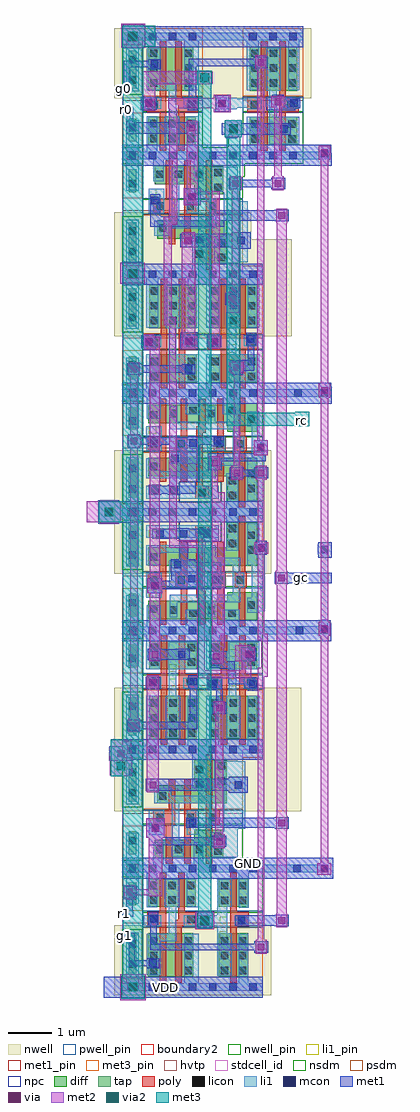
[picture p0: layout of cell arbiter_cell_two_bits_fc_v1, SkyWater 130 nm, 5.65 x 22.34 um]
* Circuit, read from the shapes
.subckt arbiter_cell_two_bits_fc_v1 GND VDD g0 g1 gc r0 r1 rc
XM1 g1 sky130_fd_sc_hd__nand2_1_13/A GND GND sky130_fd_pr__nfet_01v8 w=0.65 l=0.15
XM2 n1 sky130_fd_sc_hd__or4_1_8/A GND GND sky130_fd_pr__nfet_01v8 w=0.42 l=0.15 m=4
XM3 n2 sky130_fd_sc_hd__nand2_1_5/A GND GND sky130_fd_pr__nfet_01v8 w=0.42 l=0.15 m=4
XM4 g0 sky130_fd_sc_hd__nor2_1_1/A GND GND sky130_fd_pr__nfet_01v8 w=0.65 l=0.15
XM5 n3 sky130_fd_sc_hd__nand2_1_5/B GND GND sky130_fd_pr__nfet_01v8 w=0.65 l=0.15
XM6 n4 sky130_fd_sc_hd__or4_1_8/A GND GND sky130_fd_pr__nfet_01v8 w=0.65 l=0.15
XM7 n5 r1 GND GND sky130_fd_pr__nfet_01v8 w=0.42 l=0.15
XM8 n6 gc GND GND sky130_fd_pr__nfet_01v8 w=0.42 l=0.15
XM9 GND sky130_fd_sc_hd__nor2_1_1/A g1 GND sky130_fd_pr__nfet_01v8 w=0.65 l=0.15
XM10 GND sky130_fd_sc_hd__nand2_1_6/A g0 GND sky130_fd_pr__nfet_01v8 w=0.65 l=0.15
XM11 sky130_fd_sc_hd__or4_1_8/A sky130_fd_sc_hd__nand2_1_5/A n3 GND sky130_fd_pr__nfet_01v8 w=0.65 l=0.15
XM12 sky130_fd_sc_hd__nand2_1_5/A sky130_fd_sc_hd__nand2_1_12/A n4 GND sky130_fd_pr__nfet_01v8 w=0.65 l=0.15
XM13 GND gc n5 GND sky130_fd_pr__nfet_01v8 w=0.42 l=0.15
XM14 GND r0 n6 GND sky130_fd_pr__nfet_01v8 w=0.42 l=0.15
XM15 sky130_fd_sc_hd__nand2_1_5/B n5 GND GND sky130_fd_pr__nfet_01v8 w=0.65 l=0.15
XM16 sky130_fd_sc_hd__nand2_1_12/A n6 GND GND sky130_fd_pr__nfet_01v8 w=0.65 l=0.15
XM17 n7 r1 GND GND sky130_fd_pr__nfet_01v8 w=0.65 l=0.15
XM18 n8 r0 GND GND sky130_fd_pr__nfet_01v8 w=0.65 l=0.15
XM19 GND gc sky130_fd_sc_hd__nor2_1_1/A GND sky130_fd_pr__nfet_01v8 w=0.65 l=0.15
XM20 sky130_fd_sc_hd__nand2_1_13/A n1 GND GND sky130_fd_pr__nfet_01v8 w=0.65 l=0.15
XM21 sky130_fd_sc_hd__nand2_1_6/A n2 GND GND sky130_fd_pr__nfet_01v8 w=0.65 l=0.15
XM22 sky130_fd_sc_hd__nand2_1_15/B sky130_fd_sc_hd__nand2_1_6/A n7 GND sky130_fd_pr__nfet_01v8 w=0.65 l=0.15
XM23 sky130_fd_sc_hd__nand2_1_15/A sky130_fd_sc_hd__nand2_1_13/A n8 GND sky130_fd_pr__nfet_01v8 w=0.65 l=0.15
XM24 n9 sky130_fd_sc_hd__nand2_1_15/B GND GND sky130_fd_pr__nfet_01v8 w=0.65 l=0.15
XM25 rc sky130_fd_sc_hd__nand2_1_15/A n9 GND sky130_fd_pr__nfet_01v8 w=0.65 l=0.15
XM26 n10 sky130_fd_sc_hd__nand2_1_13/A g1 VDD sky130_fd_pr__pfet_01v8_hvt w=1 l=0.15
XM27 n11 sky130_fd_sc_hd__or4_1_8/A n1 VDD sky130_fd_pr__pfet_01v8_hvt w=0.42 l=0.15
XM28 n12 sky130_fd_sc_hd__nand2_1_5/A n2 VDD sky130_fd_pr__pfet_01v8_hvt w=0.42 l=0.15
XM29 n13 sky130_fd_sc_hd__nor2_1_1/A g0 VDD sky130_fd_pr__pfet_01v8_hvt w=1 l=0.15
XM30 sky130_fd_sc_hd__or4_1_8/A sky130_fd_sc_hd__nand2_1_5/B VDD VDD sky130_fd_pr__pfet_01v8_hvt w=1 l=0.15
XM31 sky130_fd_sc_hd__nand2_1_5/A sky130_fd_sc_hd__or4_1_8/A VDD VDD sky130_fd_pr__pfet_01v8_hvt w=1 l=0.15
XM32 n14 r1 n5 VDD sky130_fd_pr__pfet_01v8_hvt w=0.42 l=0.15
XM33 n15 gc n6 VDD sky130_fd_pr__pfet_01v8_hvt w=0.42 l=0.15
XM34 VDD sky130_fd_sc_hd__nor2_1_1/A n10 VDD sky130_fd_pr__pfet_01v8_hvt w=1 l=0.15
XM35 VDD sky130_fd_sc_hd__nand2_1_6/A n13 VDD sky130_fd_pr__pfet_01v8_hvt w=1 l=0.15
XM36 VDD sky130_fd_sc_hd__nand2_1_5/A sky130_fd_sc_hd__or4_1_8/A VDD sky130_fd_pr__pfet_01v8_hvt w=1 l=0.15
XM37 VDD sky130_fd_sc_hd__nand2_1_12/A sky130_fd_sc_hd__nand2_1_5/A VDD sky130_fd_pr__pfet_01v8_hvt w=1 l=0.15
XM38 n16 sky130_fd_sc_hd__or4_1_8/A n11 VDD sky130_fd_pr__pfet_01v8_hvt w=0.42 l=0.15
XM39 n17 sky130_fd_sc_hd__nand2_1_5/A n12 VDD sky130_fd_pr__pfet_01v8_hvt w=0.42 l=0.15
XM40 VDD gc n14 VDD sky130_fd_pr__pfet_01v8_hvt w=0.42 l=0.15
XM41 VDD r0 n15 VDD sky130_fd_pr__pfet_01v8_hvt w=0.42 l=0.15
XM42 n18 sky130_fd_sc_hd__or4_1_8/A n16 VDD sky130_fd_pr__pfet_01v8_hvt w=0.42 l=0.15
XM43 n19 sky130_fd_sc_hd__nand2_1_5/A n17 VDD sky130_fd_pr__pfet_01v8_hvt w=0.42 l=0.15
XM44 sky130_fd_sc_hd__nand2_1_5/B n5 VDD VDD sky130_fd_pr__pfet_01v8_hvt w=1 l=0.15
XM45 sky130_fd_sc_hd__nand2_1_12/A n6 VDD VDD sky130_fd_pr__pfet_01v8_hvt w=1 l=0.15
XM46 VDD sky130_fd_sc_hd__or4_1_8/A n18 VDD sky130_fd_pr__pfet_01v8_hvt w=0.42 l=0.15
XM47 VDD sky130_fd_sc_hd__nand2_1_5/A n19 VDD sky130_fd_pr__pfet_01v8_hvt w=0.42 l=0.15
XM48 sky130_fd_sc_hd__nand2_1_15/B r1 VDD VDD sky130_fd_pr__pfet_01v8_hvt w=1 l=0.15
XM49 sky130_fd_sc_hd__nand2_1_15/A r0 VDD VDD sky130_fd_pr__pfet_01v8_hvt w=1 l=0.15
XM50 VDD gc sky130_fd_sc_hd__nor2_1_1/A VDD sky130_fd_pr__pfet_01v8_hvt w=1 l=0.15
XM51 sky130_fd_sc_hd__nand2_1_13/A n1 VDD VDD sky130_fd_pr__pfet_01v8_hvt w=1 l=0.15
XM52 sky130_fd_sc_hd__nand2_1_6/A n2 VDD VDD sky130_fd_pr__pfet_01v8_hvt w=1 l=0.15
XM53 VDD sky130_fd_sc_hd__nand2_1_6/A sky130_fd_sc_hd__nand2_1_15/B VDD sky130_fd_pr__pfet_01v8_hvt w=1 l=0.15
XM54 VDD sky130_fd_sc_hd__nand2_1_13/A sky130_fd_sc_hd__nand2_1_15/A VDD sky130_fd_pr__pfet_01v8_hvt w=1 l=0.15
XM55 rc sky130_fd_sc_hd__nand2_1_15/B VDD VDD sky130_fd_pr__pfet_01v8_hvt w=1 l=0.15
XM56 VDD sky130_fd_sc_hd__nand2_1_15/A rc VDD sky130_fd_pr__pfet_01v8_hvt w=1 l=0.15
.ends

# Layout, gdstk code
from math import pi, radians
import gdstk
lib = gdstk.Library(unit=1e-6, precision=1e-09)
def R(c, l, rs):  # rectangles x0, y0, x1, y1
    for r in rs: c.add(gdstk.rectangle(r[:2], r[2:], *l))
def A(c, l, x, y, w, h, nx, ny, dx, dy):  # array of equal rectangles
    R(c, l, [(x+i*dx, y+j*dy, x+i*dx+w, y+j*dy+h) for i in range(nx) for j in range(ny)])
def P(c, l, *ps):  # polygons
    for p in ps: c.add(gdstk.Polygon(p, *l))
nwell_pin = (64, 16)
nwell = (64, 20)
diff = (65, 20)
tap = (65, 44)
poly = (66, 20)
licon = (66, 44)
li1_pin = (67, 16)
li1 = (67, 20)
mcon = (67, 44)
met1_pin = (68, 16)
met1 = (68, 20)
via = (68, 44)
met2 = (69, 20)
via2 = (69, 44)
met3_pin = (70, 16)
met3 = (70, 20)
hvtp = (78, 44)
stdcell_id = (81, 4)
nsdm = (93, 44)
psdm = (94, 20)
npc = (95, 20)
pwell_pin = (122, 16)
boundary2 = (236, 0)

sky130_fd_sc_hd__inv_1 = lib.new_cell('sky130_fd_sc_hd__inv_1')
R(sky130_fd_sc_hd__inv_1, nwell_pin, [(0.145,2.635,0.315,2.805), (0.145,2.635,0.315,2.805)])
R(sky130_fd_sc_hd__inv_1, nwell, [(-0.19,1.305,1.57,2.91)])
R(sky130_fd_sc_hd__inv_1, diff, [(0.34,0.235,1.01,0.885), (0.34,1.485,1.01,2.485)])
P(sky130_fd_sc_hd__inv_1, poly, [(0.75,2.615),(0.6,2.615),(0.6,1.325),(0.32,1.325),(0.32,0.995),(0.6,0.995),(0.6,0.105),(0.75,0.105)])
A(sky130_fd_sc_hd__inv_1, licon, 0.38, 1.575, 0.17, 0.17, 1, 3, 0, 0.34)
A(sky130_fd_sc_hd__inv_1, licon, 0.8, 1.575, 0.17, 0.17, 1, 3, 0, 0.34)
R(sky130_fd_sc_hd__inv_1, licon, [(0.38,0.315,0.55,0.485), (0.8,0.315,0.97,0.485), (0.38,0.655,0.55,0.825), (0.8,0.655,0.97,0.825), (0.4,1.075,0.57,1.245)])
R(sky130_fd_sc_hd__inv_1, li1_pin, [(0.36,1.105,0.53,1.275), (0.82,1.105,0.99,1.275), (0.82,1.445,0.99,1.615)])
R(sky130_fd_sc_hd__inv_1, li1, [(0,-0.085,1.38,0.085), (0.32,0.005,0.55,0.905), (0.32,1.075,0.65,1.315), (0.34,1.495,0.55,2.675), (0,2.635,1.38,2.805)])
P(sky130_fd_sc_hd__inv_1, li1, [(1.05,2.465),(0.72,2.465),(0.72,1.485),(0.82,1.485),(0.82,0.885),(0.72,0.885),(0.72,0.255),(1.05,0.255)])
A(sky130_fd_sc_hd__inv_1, mcon, 0.145, -0.085, 0.17, 0.17, 3, 2, 0.46, 2.72)
R(sky130_fd_sc_hd__inv_1, met1_pin, [(0.145,-0.085,0.315,0.085), (0.145,-0.085,0.315,0.085), (0.145,2.635,0.315,2.805), (0.145,2.635,0.315,2.805)])
R(sky130_fd_sc_hd__inv_1, hvtp, [(0,1.25,1.38,2.72)])
R(sky130_fd_sc_hd__inv_1, stdcell_id, [(0,0,1.38,2.72)])
R(sky130_fd_sc_hd__inv_1, nsdm, [(0,-0.19,1.38,1.015)])
R(sky130_fd_sc_hd__inv_1, psdm, [(0,1.355,1.38,2.91)])
R(sky130_fd_sc_hd__inv_1, npc, [(0,0.975,1.38,1.345)])
R(sky130_fd_sc_hd__inv_1, pwell_pin, [(0.145,-0.085,0.315,0.085), (0.145,-0.085,0.315,0.085)])
R(sky130_fd_sc_hd__inv_1, boundary2, [(0,0,1.38,2.72)])
sky130_fd_sc_hd__inv_1.add(gdstk.FlexPath([(0,2.72),(1.38,2.72)], 0.48, ends="flush", simple_path=True, layer=68, datatype=20))  # met1
sky130_fd_sc_hd__inv_1.add(gdstk.FlexPath([(0,0),(1.38,0)], 0.48, ends="flush", simple_path=True, layer=68, datatype=20))  # met1
sky130_fd_sc_hd__inv_1.add(gdstk.Label('Y', (0.905,1.53), layer=67, texttype=5))
sky130_fd_sc_hd__inv_1.add(gdstk.Label('Y', (0.905,1.19), layer=67, texttype=5))
sky130_fd_sc_hd__inv_1.add(gdstk.Label('A', (0.445,1.19), layer=67, texttype=5))
sky130_fd_sc_hd__inv_1.add(gdstk.Label('VPB', (0.23,2.72), layer=64, texttype=5))
sky130_fd_sc_hd__inv_1.add(gdstk.Label('VNB', (0.23,0), layer=64, texttype=59))
sky130_fd_sc_hd__inv_1.add(gdstk.Label('VGND', (0.23,0), layer=68, texttype=5))
sky130_fd_sc_hd__inv_1.add(gdstk.Label('VPWR', (0.23,2.72), layer=68, texttype=5))
sky130_fd_sc_hd__inv_1.add(gdstk.Label('inv_1', (0,0), layer=83, texttype=44))

sky130_fd_sc_hd__nor2_1 = lib.new_cell('sky130_fd_sc_hd__nor2_1')
R(sky130_fd_sc_hd__nor2_1, nwell_pin, [(0.15,2.635,0.32,2.805)])
R(sky130_fd_sc_hd__nor2_1, nwell, [(-0.19,1.305,1.57,2.91)])
R(sky130_fd_sc_hd__nor2_1, diff, [(0.135,0.235,1.225,0.885), (0.135,1.485,1.165,2.485)])
P(sky130_fd_sc_hd__nor2_1, poly, [(1.275,1.325),(0.905,1.325),(0.905,2.615),(0.755,2.615),(0.755,1.175),(0.815,1.175),(0.815,0.105),(0.965,0.105),(0.965,0.995),(1.275,0.995)],
  [(0.545,2.615),(0.395,2.615),(0.395,1.325),(0.11,1.325),(0.11,0.995),(0.395,0.995),(0.395,0.105),(0.545,0.105)])
A(sky130_fd_sc_hd__nor2_1, licon, 0.175, 0.305, 0.17, 0.17, 3, 2, 0.42, 0.34)
A(sky130_fd_sc_hd__nor2_1, licon, 0.175, 1.575, 0.17, 0.17, 1, 3, 0, 0.34)
A(sky130_fd_sc_hd__nor2_1, licon, 0.955, 1.575, 0.17, 0.17, 1, 3, 0, 0.34)
R(sky130_fd_sc_hd__nor2_1, licon, [(0.185,1.075,0.355,1.245), (1.025,1.075,1.195,1.245)])
R(sky130_fd_sc_hd__nor2_1, li1_pin, [(0.145,1.105,0.315,1.275), (1.065,1.105,1.235,1.275), (0.15,2.125,0.32,2.295)])
R(sky130_fd_sc_hd__nor2_1, li1, [(0.085,1.075,0.435,1.325), (0.945,1.075,1.295,1.325)])
P(sky130_fd_sc_hd__nor2_1, li1, [(1.38,0.085),(1.285,0.085),(1.285,0.895),(1.015,0.895),(1.015,0.085),(0.345,0.085),(0.345,0.895),(0.105,0.895),(0.105,0.085),(0,0.085),(0,-0.085),(1.38,-0.085)],
  [(1.38,2.805),(0,2.805),(0,2.635),(0.955,2.635),(0.955,1.495),(1.285,1.495),(1.285,2.635),(1.38,2.635)],
  [(0.845,0.895),(0.775,0.895),(0.775,1.665),(0.425,1.665),(0.425,2.45),(0.095,2.45),(0.095,1.495),(0.605,1.495),(0.605,0.895),(0.515,0.895),(0.515,0.255),(0.845,0.255)])
A(sky130_fd_sc_hd__nor2_1, mcon, 0.145, -0.085, 0.17, 0.17, 3, 2, 0.46, 2.72)
R(sky130_fd_sc_hd__nor2_1, met1_pin, [(0.15,-0.085,0.32,0.085), (0.15,2.635,0.32,2.805)])
R(sky130_fd_sc_hd__nor2_1, hvtp, [(0,1.25,1.38,2.72)])
R(sky130_fd_sc_hd__nor2_1, stdcell_id, [(0,0,1.38,2.72)])
R(sky130_fd_sc_hd__nor2_1, nsdm, [(0,-0.19,1.38,1.015)])
R(sky130_fd_sc_hd__nor2_1, psdm, [(0,1.355,1.38,2.91)])
R(sky130_fd_sc_hd__nor2_1, npc, [(0,0.975,1.38,1.345)])
R(sky130_fd_sc_hd__nor2_1, pwell_pin, [(0.15,-0.085,0.32,0.085)])
R(sky130_fd_sc_hd__nor2_1, boundary2, [(0,0,1.38,2.72)])
sky130_fd_sc_hd__nor2_1.add(gdstk.FlexPath([(0,2.72),(1.38,2.72)], 0.48, ends="flush", simple_path=True, layer=68, datatype=20))  # met1
sky130_fd_sc_hd__nor2_1.add(gdstk.FlexPath([(0,0),(1.38,0)], 0.48, ends="flush", simple_path=True, layer=68, datatype=20))  # met1
sky130_fd_sc_hd__nor2_1.add(gdstk.Label('B', (0.23,1.19), layer=67, texttype=5))
sky130_fd_sc_hd__nor2_1.add(gdstk.Label('Y', (0.235,2.21), layer=67, texttype=5))
sky130_fd_sc_hd__nor2_1.add(gdstk.Label('A', (1.15,1.19), layer=67, texttype=5))
sky130_fd_sc_hd__nor2_1.add(gdstk.Label('VPB', (0.235,2.72), layer=64, texttype=5))
sky130_fd_sc_hd__nor2_1.add(gdstk.Label('VNB', (0.235,0), layer=64, texttype=59))
sky130_fd_sc_hd__nor2_1.add(gdstk.Label('VGND', (0.23,0), layer=68, texttype=5))
sky130_fd_sc_hd__nor2_1.add(gdstk.Label('VPWR', (0.23,2.72), layer=68, texttype=5))
sky130_fd_sc_hd__nor2_1.add(gdstk.Label('nor2_1', (0,0), layer=83, texttype=44))

sky130_fd_sc_hd__or2_1 = lib.new_cell('sky130_fd_sc_hd__or2_1')
R(sky130_fd_sc_hd__or2_1, nwell_pin, [(0.145,2.635,0.315,2.805)])
R(sky130_fd_sc_hd__or2_1, nwell, [(-0.19,1.305,2.49,2.91)])
P(sky130_fd_sc_hd__or2_1, diff, [(1.855,0.885),(1.185,0.885),(1.185,0.655),(0.28,0.655),(0.28,0.235),(1.855,0.235)],
  [(1.935,2.485),(1.185,2.485),(1.185,1.905),(0.34,1.905),(0.34,1.485),(1.935,1.485)])
P(sky130_fd_sc_hd__or2_1, poly, [(0.75,2.035),(0.6,2.035),(0.6,1.325),(0.25,1.325),(0.25,0.995),(0.54,0.995),(0.54,0.105),(0.69,0.105),(0.69,0.995),(0.75,0.995)],
  [(1.775,1.325),(1.595,1.325),(1.595,2.615),(1.445,2.615),(1.445,0.105),(1.595,0.105),(1.595,0.995),(1.775,0.995)],
  [(1.23,1.325),(1.11,1.325),(1.11,2.035),(0.96,2.035),(0.96,0.105),(1.11,0.105),(1.11,0.995),(1.23,0.995)])
R(sky130_fd_sc_hd__or2_1, licon, [(1.645,0.305,1.815,0.475), (0.32,0.345,0.49,0.515), (0.74,0.345,0.91,0.515), (1.22,0.345,1.39,0.515), (1.645,0.645,1.815,0.815), (0.33,1.075,0.5,1.245), (1.01,1.075,1.18,1.245), (1.525,1.075,1.695,1.245), (0.38,1.575,0.55,1.745), (1.225,1.835,1.395,2.005), (1.725,1.915,1.895,2.085), (1.225,2.175,1.395,2.345), (1.725,2.255,1.895,2.425)])
R(sky130_fd_sc_hd__or2_1, li1_pin, [(0.145,0.765,0.315,0.935), (1.065,0.765,1.235,0.935), (0.145,1.105,0.315,1.275), (1.065,1.105,1.235,1.275), (1.985,1.785,2.155,1.955)])
R(sky130_fd_sc_hd__or2_1, li1, [(0.145,0.765,0.5,1.325), (1.01,0.765,1.275,1.325)])
P(sky130_fd_sc_hd__or2_1, li1, [(2.18,2.465),(1.645,2.465),(1.645,1.845),(1.865,1.845),(1.865,0.825),(1.565,0.825),(1.565,0.255),(2.18,0.255)],
  [(1.695,1.665),(0.66,1.665),(0.66,1.84),(0.27,1.84),(0.27,1.495),(0.67,1.495),(0.67,0.265),(0.95,0.265),(0.95,0.595),(0.84,0.595),(0.84,1.495),(1.525,1.495),(1.525,0.995),(1.695,0.995)],
  [(2.3,2.805),(0,2.805),(0,2.635),(1.145,2.635),(1.145,1.835),(1.475,1.835),(1.475,2.635),(2.3,2.635)],
  [(2.3,0.085),(1.395,0.085),(1.395,0.595),(1.18,0.595),(1.18,0.085),(0.49,0.085),(0.49,0.595),(0.25,0.595),(0.25,0.085),(0,0.085),(0,-0.085),(2.3,-0.085)])
A(sky130_fd_sc_hd__or2_1, mcon, 0.145, -0.085, 0.17, 0.17, 5, 2, 0.46, 2.72)
R(sky130_fd_sc_hd__or2_1, met1_pin, [(0.145,-0.085,0.315,0.085), (0.145,2.635,0.315,2.805)])
R(sky130_fd_sc_hd__or2_1, hvtp, [(0,1.25,2.3,2.72)])
R(sky130_fd_sc_hd__or2_1, stdcell_id, [(0,0,2.3,2.72)])
R(sky130_fd_sc_hd__or2_1, nsdm, [(0,-0.19,2.3,1.015)])
R(sky130_fd_sc_hd__or2_1, psdm, [(0,1.355,2.3,2.91)])
R(sky130_fd_sc_hd__or2_1, npc, [(0,0.975,2.3,1.345)])
R(sky130_fd_sc_hd__or2_1, pwell_pin, [(0.145,-0.085,0.315,0.085)])
R(sky130_fd_sc_hd__or2_1, boundary2, [(0,0,2.3,2.72)])
sky130_fd_sc_hd__or2_1.add(gdstk.FlexPath([(0,2.72),(2.3,2.72)], 0.48, ends="flush", simple_path=True, layer=68, datatype=20))  # met1
sky130_fd_sc_hd__or2_1.add(gdstk.FlexPath([(0,0),(2.3,0)], 0.48, ends="flush", simple_path=True, layer=68, datatype=20))  # met1
sky130_fd_sc_hd__or2_1.add(gdstk.Label('A', (1.15,1.19), layer=67, texttype=5))
sky130_fd_sc_hd__or2_1.add(gdstk.Label('X', (2.07,1.87), layer=67, texttype=5))
sky130_fd_sc_hd__or2_1.add(gdstk.Label('B', (0.23,1.19), layer=67, texttype=5))
sky130_fd_sc_hd__or2_1.add(gdstk.Label('VPB', (0.23,2.72), layer=64, texttype=5))
sky130_fd_sc_hd__or2_1.add(gdstk.Label('VNB', (0.23,0), layer=64, texttype=59))
sky130_fd_sc_hd__or2_1.add(gdstk.Label('VGND', (0.23,0), layer=68, texttype=5))
sky130_fd_sc_hd__or2_1.add(gdstk.Label('VPWR', (0.23,2.72), layer=68, texttype=5))
sky130_fd_sc_hd__or2_1.add(gdstk.Label('or2_1', (0,0), layer=83, texttype=44))

sky130_fd_sc_hd__tapvpwr = lib.new_cell('sky130_fd_sc_hd__tapvpwrvgnd_1')
R(sky130_fd_sc_hd__tapvpwr, nwell, [(-0.19,1.305,0.65,2.91)])
R(sky130_fd_sc_hd__tapvpwr, tap, [(0.145,0.32,0.315,0.845), (0.145,1.525,0.315,2.4)])
R(sky130_fd_sc_hd__tapvpwr, licon, [(0.145,0.555,0.315,0.725), (0.145,1.645,0.315,1.815), (0.145,2.11,0.315,2.28)])
R(sky130_fd_sc_hd__tapvpwr, li1, [(0,-0.085,0.46,0.085), (0.085,0,0.375,0.81), (0.085,1.47,0.375,2.72), (0,2.635,0.46,2.805)])
R(sky130_fd_sc_hd__tapvpwr, mcon, [(0.145,-0.085,0.315,0.085), (0.145,2.635,0.315,2.805)])
R(sky130_fd_sc_hd__tapvpwr, met1_pin, [(0.105,-0.09,0.36,0.1), (0.11,2.62,0.375,2.765)])
R(sky130_fd_sc_hd__tapvpwr, met1, [(0,-0.24,0.46,0.24), (0,2.48,0.46,2.96)])
R(sky130_fd_sc_hd__tapvpwr, hvtp, [(0,1.25,0.46,2.72)])
R(sky130_fd_sc_hd__tapvpwr, stdcell_id, [(0,0,0.46,2.72)])
R(sky130_fd_sc_hd__tapvpwr, nsdm, [(0,-0.19,0.46,0.19), (0,1.395,0.46,2.53)])
R(sky130_fd_sc_hd__tapvpwr, psdm, [(0,0.19,0.46,0.975), (0,2.53,0.46,2.91)])
sky130_fd_sc_hd__tapvpwr.add(gdstk.Label('VPWR', (0.23,2.72), layer=68, texttype=5))
sky130_fd_sc_hd__tapvpwr.add(gdstk.Label('VGND', (0.23,0), layer=68, texttype=5))
sky130_fd_sc_hd__tapvpwr.add(gdstk.Label('tapvpwrvgnd_1', (0,0), layer=83, texttype=44))

sky130_fd_sc_hd__nand2_1 = lib.new_cell('sky130_fd_sc_hd__nand2_1')
R(sky130_fd_sc_hd__nand2_1, nwell_pin, [(0.14,2.635,0.31,2.805)])
R(sky130_fd_sc_hd__nand2_1, nwell, [(-0.19,1.305,1.57,2.91)])
R(sky130_fd_sc_hd__nand2_1, diff, [(0.155,0.235,1.245,0.885), (0.155,1.485,1.245,2.485)])
P(sky130_fd_sc_hd__nand2_1, poly, [(1.275,1.325),(0.985,1.325),(0.985,2.615),(0.835,2.615),(0.835,0.105),(0.985,0.105),(0.985,0.995),(1.275,0.995)],
  [(0.565,2.615),(0.415,2.615),(0.415,1.325),(0.105,1.325),(0.105,0.995),(0.415,0.995),(0.415,0.105),(0.565,0.105)])
A(sky130_fd_sc_hd__nand2_1, licon, 0.195, 1.575, 0.17, 0.17, 3, 3, 0.42, 0.34)
R(sky130_fd_sc_hd__nand2_1, licon, [(0.195,0.295,0.365,0.465), (1.035,0.295,1.205,0.465), (0.195,0.635,0.365,0.805), (1.035,0.635,1.205,0.805), (0.18,1.075,0.35,1.245), (1.02,1.075,1.19,1.245)])
A(sky130_fd_sc_hd__nand2_1, li1_pin, 0.14, 1.105, 0.17, 0.17, 3, 1, 0.46, 0)
R(sky130_fd_sc_hd__nand2_1, li1_pin, [(0.6,0.425,0.77,0.595), (0.6,0.765,0.77,0.935)])
R(sky130_fd_sc_hd__nand2_1, li1, [(0.095,1.055,0.43,1.325), (0.94,1.075,1.275,1.325)])
P(sky130_fd_sc_hd__nand2_1, li1, [(1.38,0.085),(0.395,0.085),(0.395,0.885),(0.085,0.885),(0.085,0.085),(0,0.085),(0,-0.085),(1.38,-0.085)],
  [(1.38,2.805),(0,2.805),(0,2.635),(0.085,2.635),(0.085,1.495),(0.365,1.495),(0.365,2.635),(1.035,2.635),(1.035,1.495),(1.295,1.495),(1.295,2.635),(1.38,2.635)],
  [(1.295,0.885),(0.77,0.885),(0.77,1.485),(0.865,1.485),(0.865,2.465),(0.535,2.465),(0.535,1.485),(0.6,1.485),(0.6,0.255),(1.295,0.255)])
A(sky130_fd_sc_hd__nand2_1, mcon, 0.145, -0.085, 0.17, 0.17, 3, 2, 0.46, 2.72)
R(sky130_fd_sc_hd__nand2_1, met1_pin, [(0.14,-0.085,0.31,0.085), (0.14,2.635,0.31,2.805)])
R(sky130_fd_sc_hd__nand2_1, hvtp, [(0,1.25,1.38,2.72)])
R(sky130_fd_sc_hd__nand2_1, stdcell_id, [(0,0,1.38,2.72)])
R(sky130_fd_sc_hd__nand2_1, nsdm, [(0,-0.19,1.38,1.015)])
R(sky130_fd_sc_hd__nand2_1, psdm, [(0,1.355,1.38,2.91)])
R(sky130_fd_sc_hd__nand2_1, npc, [(0,0.975,1.38,1.345)])
R(sky130_fd_sc_hd__nand2_1, pwell_pin, [(0.14,-0.085,0.31,0.085)])
R(sky130_fd_sc_hd__nand2_1, boundary2, [(0,0,1.38,2.72)])
sky130_fd_sc_hd__nand2_1.add(gdstk.FlexPath([(0,2.72),(1.38,2.72)], 0.48, ends="flush", simple_path=True, layer=68, datatype=20))  # met1
sky130_fd_sc_hd__nand2_1.add(gdstk.FlexPath([(0,0),(1.38,0)], 0.48, ends="flush", simple_path=True, layer=68, datatype=20))  # met1
sky130_fd_sc_hd__nand2_1.add(gdstk.Label('Y', (0.685,0.51), layer=67, texttype=5))
sky130_fd_sc_hd__nand2_1.add(gdstk.Label('Y', (0.685,0.85), layer=67, texttype=5))
sky130_fd_sc_hd__nand2_1.add(gdstk.Label('Y', (0.685,1.19), layer=67, texttype=5))
sky130_fd_sc_hd__nand2_1.add(gdstk.Label('B', (0.225,1.19), layer=67, texttype=5))
sky130_fd_sc_hd__nand2_1.add(gdstk.Label('A', (1.145,1.19), layer=67, texttype=5))
sky130_fd_sc_hd__nand2_1.add(gdstk.Label('VPB', (0.225,2.72), layer=64, texttype=5))
sky130_fd_sc_hd__nand2_1.add(gdstk.Label('VNB', (0.225,0), layer=64, texttype=59))
sky130_fd_sc_hd__nand2_1.add(gdstk.Label('VGND', (0.23,0), layer=68, texttype=5))
sky130_fd_sc_hd__nand2_1.add(gdstk.Label('VPWR', (0.225,2.72), layer=68, texttype=5))
sky130_fd_sc_hd__nand2_1.add(gdstk.Label('nand2_1', (0,0), layer=83, texttype=44))

sky130_fd_sc_hd__or4_1 = lib.new_cell('sky130_fd_sc_hd__or4_1')
R(sky130_fd_sc_hd__or4_1, nwell_pin, [(0.15,2.635,0.32,2.805)])
R(sky130_fd_sc_hd__or4_1, nwell, [(-0.19,1.305,2.95,2.91)])
P(sky130_fd_sc_hd__or4_1, diff, [(2.625,0.885),(1.94,0.885),(1.94,0.685),(0.135,0.685),(0.135,0.265),(1.94,0.265),(1.94,0.235),(2.625,0.235)],
  [(2.625,2.485),(1.94,2.485),(1.94,1.905),(0.135,1.905),(0.135,1.485),(2.625,1.485)])
P(sky130_fd_sc_hd__or4_1, poly, [(2.39,1.325),(2.355,1.325),(2.355,2.615),(2.205,2.615),(2.205,1.325),(2.115,1.325),(2.115,0.995),(2.205,0.995),(2.205,0.105),(2.355,0.105),(2.355,0.995),(2.39,0.995)],
  [(1.905,1.325),(1.865,1.325),(1.865,2.035),(1.715,2.035),(1.715,1.325),(1.635,1.325),(1.635,0.995),(1.715,0.995),(1.715,0.135),(1.865,0.135),(1.865,0.995),(1.905,0.995)],
  [(1.535,2.415),(1.205,2.415),(1.205,2.145),(1.235,2.145),(1.235,0.76),(1.295,0.76),(1.295,0.135),(1.445,0.135),(1.445,0.905),(1.44,0.905),(1.44,0.91),(1.385,0.91),(1.385,2.145),(1.535,2.145)],
  [(1.025,2.035),(0.875,2.035),(0.875,1.325),(0.755,1.325),(0.755,0.995),(0.875,0.995),(0.875,0.135),(1.025,0.135)],
  [(0.545,2.035),(0.395,2.035),(0.395,1.325),(0.125,1.325),(0.125,0.995),(0.395,0.995),(0.395,0.135),(0.545,0.135)])
R(sky130_fd_sc_hd__or4_1, licon, [(1.075,0.315,1.245,0.485), (1.965,0.315,2.135,0.485), (0.625,0.385,0.795,0.555), (1.495,0.385,1.665,0.555), (0.175,0.415,0.345,0.585), (2.405,0.505,2.575,0.675), (0.175,1.075,0.345,1.245), (0.805,1.075,0.975,1.245), (1.685,1.075,1.855,1.245), (2.165,1.075,2.335,1.245), (0.175,1.6,0.345,1.77), (2.405,1.76,2.575,1.93), (1.98,1.915,2.15,2.085), (2.405,2.1,2.575,2.27), (1.285,2.195,1.455,2.365), (1.98,2.255,2.15,2.425)])
A(sky130_fd_sc_hd__or4_1, li1_pin, 0.15, 1.105, 0.17, 0.17, 4, 1, 0.46, 0)
A(sky130_fd_sc_hd__or4_1, li1_pin, 0.15, 2.125, 0.17, 0.17, 3, 1, 0.46, 0)
R(sky130_fd_sc_hd__or4_1, li1_pin, [(0.15,0.765,0.32,0.935), (0.61,1.445,0.78,1.615), (1.07,1.445,1.24,1.615), (2.45,1.785,2.62,1.955)])
R(sky130_fd_sc_hd__or4_1, li1, [(0.09,0.755,0.44,1.325), (0.61,0.995,1.32,1.615), (1.49,0.995,1.895,1.325), (0.09,2.125,1.745,2.415)])
P(sky130_fd_sc_hd__or4_1, li1, [(2.76,0.085),(2.215,0.085),(2.215,0.485),(1.835,0.485),(1.835,0.085),(1.325,0.085),(1.325,0.485),(0.995,0.485),(0.995,0.085),(0.425,0.085),(0.425,0.585),(0.095,0.585),(0.095,0.085),(0,0.085),(0,-0.085),(2.76,-0.085)],
  [(2.76,2.805),(0,2.805),(0,2.635),(1.915,2.635),(1.915,1.835),(2.195,1.835),(2.195,2.635),(2.76,2.635)],
  [(2.675,2.465),(2.405,2.465),(2.405,1.495),(2.505,1.495),(2.505,0.76),(2.405,0.76),(2.405,0.415),(2.675,0.415)],
  [(2.335,1.325),(2.235,1.325),(2.235,1.665),(1.68,1.665),(1.68,1.955),(0.09,1.955),(0.09,1.495),(0.41,1.495),(0.41,1.785),(1.51,1.785),(1.51,1.495),(2.065,1.495),(2.065,0.825),(0.625,0.825),(0.625,0.305),(0.795,0.305),(0.795,0.655),(1.495,0.655),(1.495,0.305),(1.665,0.305),(1.665,0.655),(2.235,0.655),(2.235,0.995),(2.335,0.995)])
A(sky130_fd_sc_hd__or4_1, mcon, 0.145, -0.085, 0.17, 0.17, 6, 2, 0.46, 2.72)
R(sky130_fd_sc_hd__or4_1, met1_pin, [(0.15,-0.085,0.32,0.085), (0.15,2.635,0.32,2.805)])
R(sky130_fd_sc_hd__or4_1, hvtp, [(0,1.25,2.76,2.72)])
R(sky130_fd_sc_hd__or4_1, stdcell_id, [(0,0,2.76,2.72)])
R(sky130_fd_sc_hd__or4_1, nsdm, [(0,-0.19,2.76,1.015)])
P(sky130_fd_sc_hd__or4_1, psdm, [(2.76,2.91),(1.81,2.91),(1.81,2.035),(0.845,2.035),(0.845,2.495),(1.81,2.495),(1.81,2.91),(0,2.91),(0,1.355),(2.76,1.355)])
R(sky130_fd_sc_hd__or4_1, npc, [(0,0.975,2.76,1.345), (0.845,2.035,1.81,2.495)])
R(sky130_fd_sc_hd__or4_1, pwell_pin, [(0.15,-0.085,0.32,0.085)])
R(sky130_fd_sc_hd__or4_1, boundary2, [(0,0,2.76,2.72)])
sky130_fd_sc_hd__or4_1.add(gdstk.FlexPath([(0,2.72),(2.76,2.72)], 0.48, ends="flush", simple_path=True, layer=68, datatype=20))  # met1
sky130_fd_sc_hd__or4_1.add(gdstk.FlexPath([(0,0),(2.76,0)], 0.48, ends="flush", simple_path=True, layer=68, datatype=20))  # met1
sky130_fd_sc_hd__or4_1.add(gdstk.Label('C', (1.155,1.19), layer=67, texttype=5))
sky130_fd_sc_hd__or4_1.add(gdstk.Label('A', (1.615,1.19), layer=67, texttype=5))
sky130_fd_sc_hd__or4_1.add(gdstk.Label('X', (2.535,1.87), layer=67, texttype=5))
sky130_fd_sc_hd__or4_1.add(gdstk.Label('C', (0.695,1.19), layer=67, texttype=5))
sky130_fd_sc_hd__or4_1.add(gdstk.Label('B', (1.155,2.21), layer=67, texttype=5))
sky130_fd_sc_hd__or4_1.add(gdstk.Label('B', (0.695,2.21), layer=67, texttype=5))
sky130_fd_sc_hd__or4_1.add(gdstk.Label('C', (0.695,1.53), layer=67, texttype=5))
sky130_fd_sc_hd__or4_1.add(gdstk.Label('B', (0.235,2.21), layer=67, texttype=5))
sky130_fd_sc_hd__or4_1.add(gdstk.Label('C', (1.155,1.53), layer=67, texttype=5))
sky130_fd_sc_hd__or4_1.add(gdstk.Label('D', (0.235,1.19), layer=67, texttype=5))
sky130_fd_sc_hd__or4_1.add(gdstk.Label('D', (0.235,0.85), layer=67, texttype=5))
sky130_fd_sc_hd__or4_1.add(gdstk.Label('VPWR', (0.235,2.72), layer=68, texttype=5))
sky130_fd_sc_hd__or4_1.add(gdstk.Label('VGND', (0.235,0), layer=68, texttype=5))
sky130_fd_sc_hd__or4_1.add(gdstk.Label('VPB', (0.235,2.72), layer=64, texttype=5))
sky130_fd_sc_hd__or4_1.add(gdstk.Label('VNB', (0.235,0), layer=64, texttype=59))
sky130_fd_sc_hd__or4_1.add(gdstk.Label('or4_1', (0,0), layer=83, texttype=44))

arbiter_cell_two_bits_fc = lib.new_cell('arbiter_cell_two_bits_fc_v1')
R(arbiter_cell_two_bits_fc, nwell, [(23.285,12.815,23.995,14.36), (23.285,14.36,23.9,14.42), (23.285,17.03,27.575,19.335), (23.285,19.335,25.39,19.78), (25.825,19.335,27.575,19.545), (25.83,19.545,27.575,19.86), (23.285,19.78,25.395,19.86), (23.285,22.47,23.995,25.3), (23.285,27.91,27.35,30.13), (23.285,30.13,23.995,30.74), (23.285,33.35,23.475,33.53), (23.9,33.35,26.81,33.53), (23.285,33.53,26.81,34.955)])
R(arbiter_cell_two_bits_fc, poly, [(26.405,19.84,26.485,19.995)])
R(arbiter_cell_two_bits_fc, li1, [(24.425,12.92,25.42,13.09), (24.095,13.47,24.265,13.64), (25.635,14.39,25.815,14.405), (24.915,14.405,25.815,14.65), (23.97,14.425,24.37,14.505), (26.115,14.445,26.29,14.62), (23.97,14.505,24.27,14.65), (24.1,14.65,24.27,14.66), (26.55,15.64,28.185,15.81), (24.08,16.49,24.39,16.8), (25.8,16.63,26.29,16.945), (25,16.68,25.175,16.855), (25.975,16.945,26.29,18.175), (25.4,19.15,25.51,19.29), (26.38,19.855,26.55,20.025), (25.465,19.86,25.635,19.99), (24.07,19.87,24.28,20.08), (24.905,19.91,25.2,20.08), (25.465,19.99,25.69,20.03), (25.51,20.03,25.69,20.04), (25.46,20.04,25.69,20.11), (25.02,20.08,25.19,20.09), (24.53,20.4,25.185,20.8), (26.1,20.45,26.27,20.555), (26.31,20.53,26.48,20.555), (26.1,20.555,26.48,20.65), (26.195,20.65,26.48,20.7), (26.195,20.7,26.405,20.745), (26.205,20.745,26.405,20.755), (23.475,21.08,27.635,21.1), (23.475,21.1,28.185,21.25), (27.345,21.25,28.185,21.27), (28.015,21.27,28.185,23.11), (26.57,21.61,26.74,22.96), (24.12,22.095,24.32,22.295), (25.52,22.25,25.69,22.42), (24.98,22.27,25.15,22.44), (24.66,22.59,24.83,22.76), (26.555,22.96,26.755,23.16), (25.34,23.295,25.51,23.325), (24.255,23.3,24.425,23.47), (24.795,23.3,24.965,23.47), (25.225,23.325,25.51,23.465), (25.225,23.465,25.34,23.47), (25.225,23.47,25.395,23.495), (23.525,23.8,26.54,23.97), (26.56,24.14,26.73,25.31), (24.515,24.295,25.425,24.465), (24.135,24.305,24.305,24.475), (24.575,24.465,24.745,24.475), (24.595,25.025,24.765,25.195), (25.455,25.28,25.815,25.36), (24.07,25.31,24.33,25.42), (26.44,25.31,26.73,25.48), (25.455,25.36,25.535,25.37), (25.455,25.37,25.795,25.42), (25.01,25.375,25.18,25.42), (24.07,25.42,25.795,25.585), (24.07,25.585,25.74,25.59), (24.07,25.59,24.33,25.755), (23.475,26.52,28.185,26.69), (24.91,27.07,25.08,27.24), (23.97,27.66,24.205,27.925), (24.88,27.67,25.13,27.92), (25.485,27.685,25.685,27.885), (26.34,27.755,26.51,27.925), (26.375,28.15,26.545,28.425), (25.89,28.65,26.105,28.865), (26.035,29.595,26.35,30.68), (25.8,30.68,26.35,30.995), (24.14,30.925,24.315,31.1), (24.945,30.97,25.21,31.235), (27.07,31.96,28.205,31.985), (23.475,31.985,28.205,32.13), (28.015,32.13,28.185,32.17), (27.075,32.555,27.275,32.755), (25.63,33.105,26.095,33.14), (23.96,33.125,24.2,33.365), (25,33.14,25.17,33.31), (25.63,33.14,26.52,33.345), (27.32,33.16,27.49,33.33), (25.63,33.345,26.095,33.365), (23.56,33.515,23.735,34.37), (24.125,34.05,24.295,34.22), (25.23,34.68,26.67,34.705), (25.17,34.705,26.67,34.825), (25.17,34.825,26.325,34.85)])
A(arbiter_cell_two_bits_fc, mcon, 23.62, 21.08, 0.17, 0.17, 1, 3, 0, 2.72)
R(arbiter_cell_two_bits_fc, mcon, [(24.095,13.47,24.265,13.64), (25.275,14.44,25.445,14.61), (26.115,14.445,26.285,14.615), (24.1,14.49,24.27,14.66), (27.39,15.64,27.56,15.81), (28.015,15.64,28.185,15.81), (24.15,16.56,24.32,16.73), (25,16.68,25.17,16.85), (26.045,17.55,26.215,17.72), (26.38,19.855,26.55,20.025), (25.465,19.86,25.635,20.03), (24.09,19.89,24.26,20.06), (25.02,19.92,25.19,20.09), (26.31,20.53,26.48,20.7), (24.75,20.535,24.92,20.705), (27.445,21.08,27.615,21.25), (28.015,21.1,28.185,21.27), (24.135,22.11,24.305,22.28), (25.52,22.25,25.69,22.42), (24.98,22.27,25.15,22.44), (24.66,22.59,24.83,22.76), (28.015,22.94,28.185,23.11), (26.57,22.975,26.74,23.145), (25.34,23.295,25.51,23.465), (24.255,23.3,24.425,23.47), (24.795,23.3,24.965,23.47), (24.135,24.305,24.305,24.475), (24.575,24.305,24.745,24.475), (24.595,25.025,24.765,25.195), (26.56,25.27,26.73,25.44), (25.01,25.375,25.18,25.545), (24.12,25.42,24.29,25.59), (25.57,25.42,25.74,25.59), (27.41,26.52,27.58,26.69), (28.015,26.52,28.185,26.69), (24.91,27.07,25.08,27.24), (24,27.69,24.17,27.86), (25.5,27.7,25.67,27.87), (24.92,27.71,25.09,27.88), (26.34,27.755,26.51,27.925), (25.91,28.67,26.08,28.84), (26.105,30.01,26.275,30.18), (24.14,30.925,24.31,31.095), (24.99,31.015,25.16,31.185), (28.015,32,28.185,32.17), (27.09,32.57,27.26,32.74), (25,33.14,25.17,33.31), (25.675,33.15,25.845,33.32), (23.995,33.16,24.165,33.33), (27.32,33.16,27.49,33.33), (24.125,34.05,24.295,34.22)])
R(arbiter_cell_two_bits_fc, met1_pin, [(24.45,12.955,24.49,13.02), (23.5,14.165,23.54,14.19), (23.505,14.665,23.535,14.71), (26.335,15.84,26.395,15.85), (27.465,22.29,27.7,22.475), (23.525,33.07,23.595,33.115), (23.49,33.58,23.51,33.595)])
R(arbiter_cell_two_bits_fc, met1, [(23.055,12.765,25.405,13.245), (24.035,13.44,24.325,13.485), (23.62,13.485,24.325,13.625), (23.62,13.625,23.76,14.105), (24.035,13.625,24.325,13.67), (26.495,13.795,26.815,13.85), (24.11,13.85,26.815,14), (24.11,14,24.26,14.43), (26.495,14,26.815,14.055), (23.475,14.105,23.76,14.245), (25.15,14.33,25.585,14.735), (26.965,14.4,27.285,14.415), (26.055,14.415,27.285,14.65), (24.07,14.43,24.3,14.72), (23.475,14.615,23.72,14.755), (26.965,14.65,27.285,14.66), (23.57,14.755,23.71,15.05), (23.48,15.05,23.8,15.31), (23.935,15.485,23.995,15.965), (26.09,15.485,28.305,15.695), (26.075,15.695,28.305,15.85), (26.09,15.85,28.305,15.92), (26.095,15.92,28.305,15.935), (26.425,15.935,28.305,15.965), (25.535,16.215,25.855,16.255), (24.085,16.255,25.855,16.42), (24.02,16.42,25.855,16.435), (24.02,16.435,24.45,16.875), (25.535,16.435,25.855,16.475), (26.965,16.635,27.285,16.65), (24.94,16.65,27.285,16.885), (26.965,16.885,27.285,16.895), (25.915,17.45,26.35,17.5), (24.01,17.5,26.35,17.77), (25.915,17.77,26.35,17.825), (23.175,18.19,23.715,18.525), (23.935,18.205,23.995,18.685), (23.475,18.525,23.505,18.685), (23.585,18.865,23.905,18.91), (23.585,18.91,25.19,19.08), (23.585,19.08,23.905,19.125), (25.02,19.08,25.19,19.86), (25.535,19.265,25.855,19.525), (25.62,19.525,25.775,19.8), (26.35,19.795,26.58,19.85), (25.435,19.8,25.765,20.09), (24.01,19.84,24.34,20.11), (26.275,19.85,26.58,19.935), (24.99,19.86,25.22,20.15), (25.91,19.935,26.58,19.95), (25.905,19.95,26.58,20.085), (25.905,20.085,26.545,20.095), (25.47,20.09,25.765,20.105), (25.905,20.095,26.4,20.1), (25.905,20.1,26.075,20.21), (25.905,20.21,26.05,20.295), (25.71,20.295,26.05,20.315), (25.49,20.315,26.05,20.44), (25.475,20.44,26.05,20.46), (25.475,20.46,25.875,20.7), (26.195,20.465,26.505,20.475), (26.195,20.475,26.545,20.775), (24.06,20.49,24.38,20.505), (24.695,20.495,25.015,20.505), (24.06,20.505,25.015,20.74), (24.06,20.74,24.38,20.75), (24.695,20.74,25.015,20.755), (26.195,20.775,26.505,20.785), (23.475,20.925,23.995,21.095), (26.465,20.925,28.255,21.03), (26.145,21.03,28.255,21.08), (26.145,21.08,28.26,21.095), (23.475,21.095,28.26,21.24), (23.475,21.24,23.995,21.405), (26.395,21.24,28.26,21.34), (26.395,21.34,28.25,21.405), (28.015,21.405,28.185,21.415), (24.045,22.02,24.395,22.11), (24.045,22.11,25.74,22.31), (26.96,22.245,27.28,22.255), (26.96,22.255,28.275,22.49), (24.045,22.31,24.395,22.37), (24.595,22.31,25.74,22.33), (24.595,22.33,25.745,22.485), (24.58,22.485,25.745,22.73), (26.96,22.49,27.28,22.505), (24.58,22.73,25.14,22.8), (24.78,22.8,24.98,23.215), (27.965,22.84,28.27,22.91), (26.525,22.9,26.785,23.22), (27.955,22.91,28.27,23.14), (27.965,23.14,28.27,23.195), (24.78,23.215,25.685,23.27), (24.165,23.27,25.685,23.495), (24.165,23.495,25.01,23.5), (24.73,23.5,25.01,23.505), (22.925,23.615,23.405,23.64), (22.925,23.64,23.73,23.645), (22.925,23.645,23.995,24.125), (25.275,24.095,25.445,24.125), (22.925,24.125,23.73,24.13), (22.925,24.13,23.405,24.155), (24.075,24.275,24.365,24.295), (24.515,24.275,24.805,24.295), (24.075,24.295,25.16,24.485), (24.075,24.485,24.365,24.505), (24.515,24.485,25.16,24.505), (24.555,24.505,25.16,24.57), (24.555,24.57,25.25,25.42), (25.94,24.65,26.26,24.705), (26.495,24.65,26.815,24.705), (25.94,24.705,26.815,24.855), (25.43,24.835,25.755,25.05), (25.94,24.855,26.26,24.91), (26.495,24.855,26.815,24.91), (25.43,25.05,26.755,25.185), (25.43,25.185,26.81,25.23), (26.48,25.23,26.81,25.52), (23.615,25.345,23.875,25.42), (24.06,25.39,24.35,25.42), (25.51,25.39,25.8,25.42), (23.615,25.42,25.8,25.59), (23.615,25.59,23.875,25.665), (24.06,25.59,24.35,25.62), (24.985,25.59,25.215,25.6), (25.51,25.59,25.8,25.62), (23.475,26.365,23.995,26.845), (26.295,26.365,28.275,26.505), (26.275,26.505,28.275,26.66), (26.525,26.66,28.275,26.69), (26.41,26.69,28.275,26.755), (26.41,26.755,28.26,26.845), (23.585,27.025,23.905,27.07), (25.97,27.03,26.23,27.115), (24.85,27.04,25.14,27.07), (23.585,27.07,25.14,27.24), (25.97,27.115,26.5,27.21), (25.935,27.21,26.5,27.36), (23.585,27.24,23.905,27.285), (24.85,27.24,25.14,27.27), (26.35,27.36,26.5,27.695), (23.94,27.6,24.235,27.63), (24.81,27.61,25.22,27.635), (23.91,27.63,24.235,27.925), (24.805,27.635,25.22,27.95), (25.425,27.655,25.745,27.915), (26.31,27.695,26.54,27.985), (23.94,27.925,24.235,27.955), (24.81,27.95,25.22,27.995), (25.86,28.59,26.135,28.62), (25.83,28.62,26.165,28.895), (25.86,28.895,26.135,28.925), (23.475,29.075,23.955,29.085), (23.475,29.085,23.995,29.565), (23.475,29.565,23.955,29.615), (25.975,29.91,26.41,29.94), (24.805,29.94,26.41,30.255), (25.975,30.255,26.41,30.285), (24.11,30.415,25.81,30.555), (26.965,30.54,27.285,30.555), (24.11,30.555,27.285,30.65), (24.11,30.65,24.345,31.16), (25.575,30.65,27.285,30.79), (26.965,30.79,27.285,30.8), (24.88,30.905,25.275,31.295), (25.91,31.275,26.23,31.32), (26.88,31.275,27.2,31.32), (25.91,31.32,27.2,31.49), (25.91,31.49,26.23,31.535), (26.88,31.49,27.2,31.535), (23.79,31.805,23.995,32.285), (26.19,31.805,28.265,31.96), (27.01,31.96,28.265,32.095), (27.01,32.095,28.26,32.285), (25.845,32.445,26.105,32.46), (25.825,32.46,26.215,32.525), (25.755,32.525,27.335,32.785), (23.575,32.535,23.725,32.54), (23.575,32.54,25.24,32.805), (25.825,32.785,26.215,32.855), (23.575,32.805,23.725,33.015), (23.475,33.015,23.73,33.165), (25.6,33.045,25.92,33.425), (24.97,33.08,25.2,33.37), (26.77,33.08,27.435,33.13), (23.9,33.095,24.26,33.395), (26.77,33.13,27.55,33.16), (26.755,33.16,27.55,33.36), (26.755,33.36,27.435,33.39), (25,33.37,25.17,34.09), (26.91,33.39,27.17,33.435), (23.475,33.53,23.665,33.68), (23.51,33.68,23.66,34.06), (24.065,34.02,24.355,34.06), (26.485,34.045,26.805,34.09), (23.51,34.06,24.355,34.21), (25,34.09,26.805,34.26), (24.065,34.21,24.355,34.25), (26.485,34.26,26.805,34.305), (23.485,34.505,23.965,34.525), (23.475,34.525,23.48,35.005), (23.485,34.525,23.995,35.005), (25.16,34.525,26.405,34.675), (24.83,34.675,26.405,34.83), (24.83,34.83,26.335,34.85), (24.83,34.85,26.405,34.92), (25.265,34.92,26.405,35.005), (23.485,35.005,23.965,35.045)])
A(arbiter_cell_two_bits_fc, via, 28.025, 21.135, 0.15, 0.15, 1, 3, 0, 5.45)
R(arbiter_cell_two_bits_fc, via, [(23.64,12.93,23.79,13.08), (26.58,13.85,26.73,14), (25.285,14.45,25.435,14.6), (27.05,14.455,27.2,14.605), (23.565,15.105,23.715,15.255), (28.025,15.635,28.175,15.785), (25.62,16.27,25.77,16.42), (24.16,16.57,24.31,16.72), (27.05,16.69,27.2,16.84), (24.1,17.56,24.25,17.71), (23.37,18.28,23.52,18.43), (23.67,18.92,23.82,19.07), (25.62,19.32,25.77,19.47), (24.1,19.9,24.25,20.05), (25.56,20.495,25.71,20.645), (24.145,20.545,24.295,20.695), (26.295,20.56,26.445,20.71), (24.145,22.12,24.295,22.27), (27.045,22.3,27.195,22.45), (26.58,22.985,26.73,23.135), (23.09,23.81,23.24,23.96), (26.025,24.705,26.175,24.855), (26.58,24.705,26.73,24.855), (25.515,24.925,25.665,25.075), (26.57,25.28,26.72,25.43), (23.67,25.43,23.82,25.58), (23.67,27.08,23.82,27.23), (26.025,27.115,26.175,27.265), (23.995,27.7,24.145,27.85), (25.51,27.71,25.66,27.86), (24.915,27.715,25.065,27.865), (25.92,28.68,26.07,28.83), (23.64,29.27,23.79,29.42), (24.915,30.02,25.065,30.17), (27.05,30.595,27.2,30.745), (25,31.025,25.15,31.175), (25.995,31.33,26.145,31.48), (26.965,31.33,27.115,31.48), (25.945,32.58,26.095,32.73), (25,32.595,25.15,32.745), (25.685,33.16,25.835,33.31), (24.005,33.17,24.155,33.32), (26.965,33.2,27.115,33.35), (26.57,34.1,26.72,34.25), (23.65,34.7,23.8,34.85)])
A(arbiter_cell_two_bits_fc, met2, 27.97, 21.05, 0.26, 0.32, 1, 3, 0, 5.45)
R(arbiter_cell_two_bits_fc, met2, [(23.425,12.71,24.015,13.295), (26.525,13.765,26.785,14.085), (26.58,14.085,26.73,20.11), (25.15,14.33,25.585,14.735), (26.995,14.37,27.255,14.69), (27.005,14.69,27.24,16.605), (23.51,15.02,23.77,15.11), (24.08,15.08,24.39,15.11), (23.51,15.11,24.39,15.25), (23.51,15.25,23.77,15.34), (24.08,15.25,24.39,16.42), (27.94,15.58,28.26,15.84), (28.015,15.84,28.185,21.05), (25.565,16.185,25.825,16.505), (24.02,16.42,24.45,16.875), (25.605,16.505,25.785,19.235), (26.995,16.605,27.255,16.925), (27.005,16.925,27.24,22.215), (24.04,17.47,24.31,20.14), (23.205,17.83,23.685,17.855), (23.185,17.855,23.705,18.285), (23.205,18.285,23.685,18.67), (23.615,18.835,23.875,19.155), (23.66,19.155,23.83,25.375), (25.565,19.235,25.825,19.555), (25.19,20.08,26.425,20.255), (26.58,20.11,26.81,20.32), (25.19,20.255,25.365,23.065), (26.215,20.255,26.425,20.465), (26.66,20.32,26.81,20.95), (25.505,20.41,25.765,20.415), (25.505,20.415,25.8,20.77), (24.09,20.46,24.35,20.78), (26.055,20.465,26.505,20.8), (25.505,20.77,25.82,21.065), (24.1,20.78,24.335,22.02), (26.055,20.8,26.41,20.835), (26.58,20.95,26.81,21.1), (25.525,21.065,25.82,24.19), (26.58,21.1,26.73,22.93), (28.015,21.37,28.185,26.5), (24.045,22.02,24.395,22.37), (26.99,22.215,27.25,22.535), (24.1,22.37,24.335,27.6), (27.005,22.535,27.24,30.51), (26.495,22.93,26.815,23.19), (24.545,23.065,25.385,23.24), (26.58,23.19,26.73,24.62), (24.545,23.24,24.72,26.905), (22.955,23.625,23.385,23.645), (22.66,23.645,23.435,24.125), (22.955,24.125,23.385,24.145), (25.52,24.19,25.82,24.335), (25.52,24.335,25.665,24.84), (25.97,24.62,26.23,24.94), (26.525,24.62,26.785,24.94), (25.46,24.84,25.72,25.16), (26.025,24.94,26.175,27.06), (26.48,25.185,26.81,25.52), (23.585,25.375,23.905,25.635), (26.56,25.52,26.73,34.015), (23.66,25.635,23.83,26.995), (28.015,26.82,28.185,31.95), (24.545,26.905,24.695,28.16), (23.615,26.995,23.875,27.315), (25.94,27.06,26.26,27.32), (23.94,27.6,24.335,27.895), (24.835,27.605,25.15,30.285), (25.455,27.625,25.715,27.945), (23.94,27.895,24.2,27.955), (25.46,27.945,25.71,30.98), (24.42,28.16,24.695,28.34), (24.42,28.34,24.605,30.46), (25.86,28.44,26.155,28.925), (25.985,28.925,26.155,31.245), (23.43,29.105,23.985,29.585), (24.42,30.46,24.735,30.645), (26.995,30.51,27.255,30.83), (24.55,30.645,24.735,33.125), (24.88,30.905,25.275,30.98), (24.88,30.98,25.71,31.23), (24.88,31.23,25.275,31.295), (25.94,31.245,26.2,31.565), (26.91,31.245,27.17,31.565), (24.945,31.295,25.21,32.835), (26.955,31.565,27.125,33.145), (25.825,32.46,26.215,32.855), (25.565,33.035,25.955,33.125), (23.93,33.065,24.23,33.675), (24.53,33.125,25.955,33.35), (26.88,33.145,27.2,33.405), (25.565,33.35,25.955,33.435), (23.93,33.675,25.51,33.685), (23.93,33.685,25.545,33.965), (23.93,33.965,25.51,33.975), (26.515,34.015,26.775,34.335), (23.45,34.51,23.995,35.055)])
R(arbiter_cell_two_bits_fc, via2, [(23.62,12.905,23.82,13.105), (25.26,14.425,25.46,14.625), (23.345,17.97,23.545,18.17), (23.07,23.785,23.27,23.985), (23.62,29.245,23.82,29.445), (25.92,32.555,26.12,32.755), (25.26,33.725,25.46,33.925), (23.615,34.675,23.815,34.875)])
R(arbiter_cell_two_bits_fc, met3_pin, [(27.555,25.925,27.605,26.015)])
R(arbiter_cell_two_bits_fc, met3, [(23.455,12.74,23.985,13.27), (23.48,13.27,23.96,17.83), (25.185,14.35,25.54,14.705), (25.21,14.705,25.51,33.66), (23.205,17.83,23.96,18.685), (23.48,18.685,23.96,23.645), (22.93,23.645,23.96,24.125), (23.48,24.125,23.96,34.535), (27.43,25.845,27.76,25.86), (25.87,25.86,27.76,26.16), (25.87,26.16,26.17,32.46), (27.43,26.16,27.76,26.175), (25.825,32.46,26.215,32.855), (25.195,33.66,25.525,33.99), (23.475,34.535,24.225,35.015)])
R(arbiter_cell_two_bits_fc, hvtp, [(25.71,18.12,25.82,18.39), (24.74,18.255,25.2,18.39), (24.74,18.39,25.82,18.5), (25.1,18.5,25.55,18.77), (25.96,23.83,26.47,23.94), (25.1,29,25.55,29.27), (24.74,29.27,25.82,29.38), (24.74,29.38,25.2,29.515), (25.71,29.38,25.82,29.65)])
R(arbiter_cell_two_bits_fc, nsdm, [(25.285,14.715,25.56,15.615), (24.09,15.615,25.93,15.835), (25.915,15.835,25.93,15.93), (25.305,20.155,25.345,21.055), (23.965,21.055,26.685,21.275), (23.965,21.275,25.75,21.305), (23.965,26.465,25.75,26.495), (23.965,26.495,26.685,26.715), (25.305,26.715,25.345,27.615), (25.915,31.555,26.28,31.935), (24.09,31.935,25.285,32.155), (25.9,31.935,26.28,32.155), (25.9,32.155,26.265,32.535)])
R(arbiter_cell_two_bits_fc, psdm, [(25.225,13.115,25.56,14.365), (24.96,18.175,24.995,18.335), (24.96,18.335,25.995,18.555), (25.305,18.555,25.345,19.805), (25.75,23.775,26.685,23.995), (25.305,27.965,25.345,29.215), (24.96,29.215,25.995,29.435), (24.96,29.435,24.995,29.595)])
R(arbiter_cell_two_bits_fc, npc, [(25.225,19.82,25.395,20.19), (25.225,27.58,25.395,27.95)])
arbiter_cell_two_bits_fc.add(gdstk.Reference(sky130_fd_sc_hd__inv_1, (26.695,15.725), rotation=pi))
arbiter_cell_two_bits_fc.add(gdstk.Reference(sky130_fd_sc_hd__nor2_1, (23.935,15.725), x_reflection=True))
arbiter_cell_two_bits_fc.add(gdstk.Reference(sky130_fd_sc_hd__or2_1, (23.935,15.725)))
arbiter_cell_two_bits_fc.add(gdstk.Reference(sky130_fd_sc_hd__tapvpwr, (23.475,15.725)))
arbiter_cell_two_bits_fc.add(gdstk.Reference(sky130_fd_sc_hd__tapvpwr, (23.475,15.725), x_reflection=True))
arbiter_cell_two_bits_fc.add(gdstk.Reference(sky130_fd_sc_hd__nand2_1, (23.935,21.165), x_reflection=True))
arbiter_cell_two_bits_fc.add(gdstk.Reference(sky130_fd_sc_hd__nand2_1, (25.315,21.165), x_reflection=True))
arbiter_cell_two_bits_fc.add(gdstk.Reference(sky130_fd_sc_hd__tapvpwr, (23.475,21.165), x_reflection=True))
arbiter_cell_two_bits_fc.add(gdstk.Reference(sky130_fd_sc_hd__or4_1, (23.935,21.165)))
arbiter_cell_two_bits_fc.add(gdstk.Reference(sky130_fd_sc_hd__tapvpwr, (23.475,21.165)))
arbiter_cell_two_bits_fc.add(gdstk.Reference(sky130_fd_sc_hd__or4_1, (23.935,26.605), x_reflection=True))
arbiter_cell_two_bits_fc.add(gdstk.Reference(sky130_fd_sc_hd__tapvpwr, (23.475,26.605), x_reflection=True))
arbiter_cell_two_bits_fc.add(gdstk.Reference(sky130_fd_sc_hd__nand2_1, (23.935,26.605)))
arbiter_cell_two_bits_fc.add(gdstk.Reference(sky130_fd_sc_hd__nand2_1, (25.315,26.605)))
arbiter_cell_two_bits_fc.add(gdstk.Reference(sky130_fd_sc_hd__tapvpwr, (23.475,26.605)))
arbiter_cell_two_bits_fc.add(gdstk.Reference(sky130_fd_sc_hd__nand2_1, (26.235,32.045)))
arbiter_cell_two_bits_fc.add(gdstk.Reference(sky130_fd_sc_hd__nor2_1, (23.935,32.045)))
arbiter_cell_two_bits_fc.add(gdstk.Reference(sky130_fd_sc_hd__or2_1, (23.935,32.045), x_reflection=True))
arbiter_cell_two_bits_fc.add(gdstk.Reference(sky130_fd_sc_hd__tapvpwr, (23.475,32.045), x_reflection=True))
arbiter_cell_two_bits_fc.add(gdstk.Reference(sky130_fd_sc_hd__tapvpwr, (23.475,32.045)))
arbiter_cell_two_bits_fc.add(gdstk.Label('gc', (27.582,22.382), layer=68, texttype=5))
arbiter_cell_two_bits_fc.add(gdstk.Label('rc', (27.58,25.97), layer=70, texttype=5))
arbiter_cell_two_bits_fc.add(gdstk.Label('GND', (26.365,15.845), layer=68, texttype=5))
arbiter_cell_two_bits_fc.add(gdstk.Label('r0', (23.56,33.092), layer=68, texttype=5))
arbiter_cell_two_bits_fc.add(gdstk.Label('g0', (23.5,33.587), layer=68, texttype=5))
arbiter_cell_two_bits_fc.add(gdstk.Label('g1', (23.52,14.177), layer=68, texttype=5))
arbiter_cell_two_bits_fc.add(gdstk.Label('r1', (23.52,14.687), layer=68, texttype=5))
arbiter_cell_two_bits_fc.add(gdstk.Label('VDD', (24.47,12.987), layer=68, texttype=5))

lib.write_gds('arbiter_cell_two_bits_fc_v1.gds')
